# Generated by FakeRAM 2.0
VERSION 5.7 ;
BUSBITCHARS "[]" ;
PROPERTYDEFINITIONS
  MACRO width INTEGER ;
  MACRO depth INTEGER ;
  MACRO banks INTEGER ;
END PROPERTYDEFINITIONS
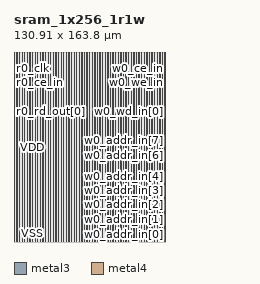
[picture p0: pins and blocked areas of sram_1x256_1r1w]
MACRO sram_1x256_1r1w
  PROPERTY width 1 ;
  PROPERTY depth 256 ;
  PROPERTY banks 1 ;
  FOREIGN sram_1x256_1r1w 0 0 ;
  SYMMETRY X Y R90 ;
  SIZE 130.910 BY 163.800 ;
  CLASS BLOCK ;
  PIN r0_addr_in[0]
    DIRECTION INPUT ;
    USE SIGNAL ;
    SHAPE ABUTMENT ;
    PORT
      LAYER metal3 ;
      RECT 0.000 0.140 0.070 0.210 ;
    END
  END r0_addr_in[0]
  PIN r0_addr_in[1]
    DIRECTION INPUT ;
    USE SIGNAL ;
    SHAPE ABUTMENT ;
    PORT
      LAYER metal3 ;
      RECT 0.000 12.600 0.070 12.670 ;
    END
  END r0_addr_in[1]
  PIN r0_addr_in[2]
    DIRECTION INPUT ;
    USE SIGNAL ;
    SHAPE ABUTMENT ;
    PORT
      LAYER metal3 ;
      RECT 0.000 25.060 0.070 25.130 ;
    END
  END r0_addr_in[2]
  PIN r0_addr_in[3]
    DIRECTION INPUT ;
    USE SIGNAL ;
    SHAPE ABUTMENT ;
    PORT
      LAYER metal3 ;
      RECT 0.000 37.520 0.070 37.590 ;
    END
  END r0_addr_in[3]
  PIN r0_addr_in[4]
    DIRECTION INPUT ;
    USE SIGNAL ;
    SHAPE ABUTMENT ;
    PORT
      LAYER metal3 ;
      RECT 0.000 49.980 0.070 50.050 ;
    END
  END r0_addr_in[4]
  PIN r0_addr_in[5]
    DIRECTION INPUT ;
    USE SIGNAL ;
    SHAPE ABUTMENT ;
    PORT
      LAYER metal3 ;
      RECT 0.000 62.440 0.070 62.510 ;
    END
  END r0_addr_in[5]
  PIN r0_addr_in[6]
    DIRECTION INPUT ;
    USE SIGNAL ;
    SHAPE ABUTMENT ;
    PORT
      LAYER metal3 ;
      RECT 0.000 74.900 0.070 74.970 ;
    END
  END r0_addr_in[6]
  PIN r0_addr_in[7]
    DIRECTION INPUT ;
    USE SIGNAL ;
    SHAPE ABUTMENT ;
    PORT
      LAYER metal3 ;
      RECT 0.000 87.360 0.070 87.430 ;
    END
  END r0_addr_in[7]
  PIN r0_rd_out[0]
    DIRECTION OUTPUT ;
    USE SIGNAL ;
    SHAPE ABUTMENT ;
    PORT
      LAYER metal3 ;
      RECT 0.000 112.280 0.070 112.350 ;
    END
  END r0_rd_out[0]
  PIN r0_ce_in
    DIRECTION INPUT ;
    USE SIGNAL ;
    SHAPE ABUTMENT ;
    PORT
      LAYER metal3 ;
      RECT 0.000 137.200 0.070 137.270 ;
    END
  END r0_ce_in
  PIN r0_clk
    DIRECTION INPUT ;
    USE SIGNAL ;
    SHAPE ABUTMENT ;
    PORT
      LAYER metal3 ;
      RECT 0.000 149.660 0.070 149.730 ;
    END
  END r0_clk
  PIN w0_addr_in[0]
    DIRECTION INPUT ;
    USE SIGNAL ;
    SHAPE ABUTMENT ;
    PORT
      LAYER metal3 ;
      RECT 130.840 0.140 130.910 0.210 ;
    END
  END w0_addr_in[0]
  PIN w0_addr_in[1]
    DIRECTION INPUT ;
    USE SIGNAL ;
    SHAPE ABUTMENT ;
    PORT
      LAYER metal3 ;
      RECT 130.840 12.600 130.910 12.670 ;
    END
  END w0_addr_in[1]
  PIN w0_addr_in[2]
    DIRECTION INPUT ;
    USE SIGNAL ;
    SHAPE ABUTMENT ;
    PORT
      LAYER metal3 ;
      RECT 130.840 25.060 130.910 25.130 ;
    END
  END w0_addr_in[2]
  PIN w0_addr_in[3]
    DIRECTION INPUT ;
    USE SIGNAL ;
    SHAPE ABUTMENT ;
    PORT
      LAYER metal3 ;
      RECT 130.840 37.520 130.910 37.590 ;
    END
  END w0_addr_in[3]
  PIN w0_addr_in[4]
    DIRECTION INPUT ;
    USE SIGNAL ;
    SHAPE ABUTMENT ;
    PORT
      LAYER metal3 ;
      RECT 130.840 49.980 130.910 50.050 ;
    END
  END w0_addr_in[4]
  PIN w0_addr_in[5]
    DIRECTION INPUT ;
    USE SIGNAL ;
    SHAPE ABUTMENT ;
    PORT
      LAYER metal3 ;
      RECT 130.840 62.440 130.910 62.510 ;
    END
  END w0_addr_in[5]
  PIN w0_addr_in[6]
    DIRECTION INPUT ;
    USE SIGNAL ;
    SHAPE ABUTMENT ;
    PORT
      LAYER metal3 ;
      RECT 130.840 74.900 130.910 74.970 ;
    END
  END w0_addr_in[6]
  PIN w0_addr_in[7]
    DIRECTION INPUT ;
    USE SIGNAL ;
    SHAPE ABUTMENT ;
    PORT
      LAYER metal3 ;
      RECT 130.840 87.360 130.910 87.430 ;
    END
  END w0_addr_in[7]
  PIN w0_wd_in[0]
    DIRECTION INPUT ;
    USE SIGNAL ;
    SHAPE ABUTMENT ;
    PORT
      LAYER metal3 ;
      RECT 130.840 112.280 130.910 112.350 ;
    END
  END w0_wd_in[0]
  PIN w0_we_in
    DIRECTION INPUT ;
    USE SIGNAL ;
    SHAPE ABUTMENT ;
    PORT
      LAYER metal3 ;
      RECT 130.840 137.200 130.910 137.270 ;
    END
  END w0_we_in
  PIN w0_ce_in
    DIRECTION INPUT ;
    USE SIGNAL ;
    SHAPE ABUTMENT ;
    PORT
      LAYER metal3 ;
      RECT 130.840 149.660 130.910 149.730 ;
    END
  END w0_ce_in
  PIN w0_clk
    DIRECTION INPUT ;
    USE SIGNAL ;
    SHAPE ABUTMENT ;
    PORT
      LAYER metal3 ;
      RECT 130.840 162.120 130.910 162.190 ;
    END
  END w0_clk
  PIN VSS
    DIRECTION INOUT ;
    USE GROUND ;
    PORT
      LAYER metal4 ;
      RECT 0.210 0.140 0.490 163.660 ;
      RECT 2.450 0.140 2.730 163.660 ;
      RECT 4.690 0.140 4.970 163.660 ;
      RECT 6.930 0.140 7.210 163.660 ;
      RECT 9.170 0.140 9.450 163.660 ;
      RECT 11.410 0.140 11.690 163.660 ;
      RECT 13.650 0.140 13.930 163.660 ;
      RECT 15.890 0.140 16.170 163.660 ;
      RECT 18.130 0.140 18.410 163.660 ;
      RECT 20.370 0.140 20.650 163.660 ;
      RECT 22.610 0.140 22.890 163.660 ;
      RECT 24.850 0.140 25.130 163.660 ;
      RECT 27.090 0.140 27.370 163.660 ;
      RECT 29.330 0.140 29.610 163.660 ;
      RECT 31.570 0.140 31.850 163.660 ;
      RECT 33.810 0.140 34.090 163.660 ;
      RECT 36.050 0.140 36.330 163.660 ;
      RECT 38.290 0.140 38.570 163.660 ;
      RECT 40.530 0.140 40.810 163.660 ;
      RECT 42.770 0.140 43.050 163.660 ;
      RECT 45.010 0.140 45.290 163.660 ;
      RECT 47.250 0.140 47.530 163.660 ;
      RECT 49.490 0.140 49.770 163.660 ;
      RECT 51.730 0.140 52.010 163.660 ;
      RECT 53.970 0.140 54.250 163.660 ;
      RECT 56.210 0.140 56.490 163.660 ;
      RECT 58.450 0.140 58.730 163.660 ;
      RECT 60.690 0.140 60.970 163.660 ;
      RECT 62.930 0.140 63.210 163.660 ;
      RECT 65.170 0.140 65.450 163.660 ;
      RECT 67.410 0.140 67.690 163.660 ;
      RECT 69.650 0.140 69.930 163.660 ;
      RECT 71.890 0.140 72.170 163.660 ;
      RECT 74.130 0.140 74.410 163.660 ;
      RECT 76.370 0.140 76.650 163.660 ;
      RECT 78.610 0.140 78.890 163.660 ;
      RECT 80.850 0.140 81.130 163.660 ;
      RECT 83.090 0.140 83.370 163.660 ;
      RECT 85.330 0.140 85.610 163.660 ;
      RECT 87.570 0.140 87.850 163.660 ;
      RECT 89.810 0.140 90.090 163.660 ;
      RECT 92.050 0.140 92.330 163.660 ;
      RECT 94.290 0.140 94.570 163.660 ;
      RECT 96.530 0.140 96.810 163.660 ;
      RECT 98.770 0.140 99.050 163.660 ;
      RECT 101.010 0.140 101.290 163.660 ;
      RECT 103.250 0.140 103.530 163.660 ;
      RECT 105.490 0.140 105.770 163.660 ;
      RECT 107.730 0.140 108.010 163.660 ;
      RECT 109.970 0.140 110.250 163.660 ;
      RECT 112.210 0.140 112.490 163.660 ;
      RECT 114.450 0.140 114.730 163.660 ;
      RECT 116.690 0.140 116.970 163.660 ;
      RECT 118.930 0.140 119.210 163.660 ;
      RECT 121.170 0.140 121.450 163.660 ;
      RECT 123.410 0.140 123.690 163.660 ;
      RECT 125.650 0.140 125.930 163.660 ;
      RECT 127.890 0.140 128.170 163.660 ;
      RECT 130.130 0.140 130.410 163.660 ;
    END
  END VSS
  PIN VDD
    DIRECTION INOUT ;
    USE POWER ;
    PORT
      LAYER metal4 ;
      RECT 0.210 0.140 0.490 163.660 ;
      RECT 2.450 0.140 2.730 163.660 ;
      RECT 4.690 0.140 4.970 163.660 ;
      RECT 6.930 0.140 7.210 163.660 ;
      RECT 9.170 0.140 9.450 163.660 ;
      RECT 11.410 0.140 11.690 163.660 ;
      RECT 13.650 0.140 13.930 163.660 ;
      RECT 15.890 0.140 16.170 163.660 ;
      RECT 18.130 0.140 18.410 163.660 ;
      RECT 20.370 0.140 20.650 163.660 ;
      RECT 22.610 0.140 22.890 163.660 ;
      RECT 24.850 0.140 25.130 163.660 ;
      RECT 27.090 0.140 27.370 163.660 ;
      RECT 29.330 0.140 29.610 163.660 ;
      RECT 31.570 0.140 31.850 163.660 ;
      RECT 33.810 0.140 34.090 163.660 ;
      RECT 36.050 0.140 36.330 163.660 ;
      RECT 38.290 0.140 38.570 163.660 ;
      RECT 40.530 0.140 40.810 163.660 ;
      RECT 42.770 0.140 43.050 163.660 ;
      RECT 45.010 0.140 45.290 163.660 ;
      RECT 47.250 0.140 47.530 163.660 ;
      RECT 49.490 0.140 49.770 163.660 ;
      RECT 51.730 0.140 52.010 163.660 ;
      RECT 53.970 0.140 54.250 163.660 ;
      RECT 56.210 0.140 56.490 163.660 ;
      RECT 58.450 0.140 58.730 163.660 ;
      RECT 60.690 0.140 60.970 163.660 ;
      RECT 62.930 0.140 63.210 163.660 ;
      RECT 65.170 0.140 65.450 163.660 ;
      RECT 67.410 0.140 67.690 163.660 ;
      RECT 69.650 0.140 69.930 163.660 ;
      RECT 71.890 0.140 72.170 163.660 ;
      RECT 74.130 0.140 74.410 163.660 ;
      RECT 76.370 0.140 76.650 163.660 ;
      RECT 78.610 0.140 78.890 163.660 ;
      RECT 80.850 0.140 81.130 163.660 ;
      RECT 83.090 0.140 83.370 163.660 ;
      RECT 85.330 0.140 85.610 163.660 ;
      RECT 87.570 0.140 87.850 163.660 ;
      RECT 89.810 0.140 90.090 163.660 ;
      RECT 92.050 0.140 92.330 163.660 ;
      RECT 94.290 0.140 94.570 163.660 ;
      RECT 96.530 0.140 96.810 163.660 ;
      RECT 98.770 0.140 99.050 163.660 ;
      RECT 101.010 0.140 101.290 163.660 ;
      RECT 103.250 0.140 103.530 163.660 ;
      RECT 105.490 0.140 105.770 163.660 ;
      RECT 107.730 0.140 108.010 163.660 ;
      RECT 109.970 0.140 110.250 163.660 ;
      RECT 112.210 0.140 112.490 163.660 ;
      RECT 114.450 0.140 114.730 163.660 ;
      RECT 116.690 0.140 116.970 163.660 ;
      RECT 118.930 0.140 119.210 163.660 ;
      RECT 121.170 0.140 121.450 163.660 ;
      RECT 123.410 0.140 123.690 163.660 ;
      RECT 125.650 0.140 125.930 163.660 ;
      RECT 127.890 0.140 128.170 163.660 ;
      RECT 130.130 0.140 130.410 163.660 ;
    END
  END VDD
  OBS
    LAYER metal1 ;
    RECT 0 0 130.910 163.800 ;
    LAYER metal2 ;
    RECT 0 0 130.910 163.800 ;
    LAYER metal3 ;
    RECT 0 0 130.910 163.800 ;
    LAYER metal4 ;
    RECT 0 0 130.910 163.800 ;
    LAYER OVERLAP ;
    RECT 0 0 130.910 163.800 ;
  END
END sram_1x256_1r1w

END LIBRARY
